VERSION 5.7 ;
  NAMESCASESENSITIVE ON ;
  NOWIREEXTENSIONATPIN ON ;
  DIVIDERCHAR "/" ;
  BUSBITCHARS "[]" ;
UNITS
  DATABASE MICRONS 200 ;
END UNITS

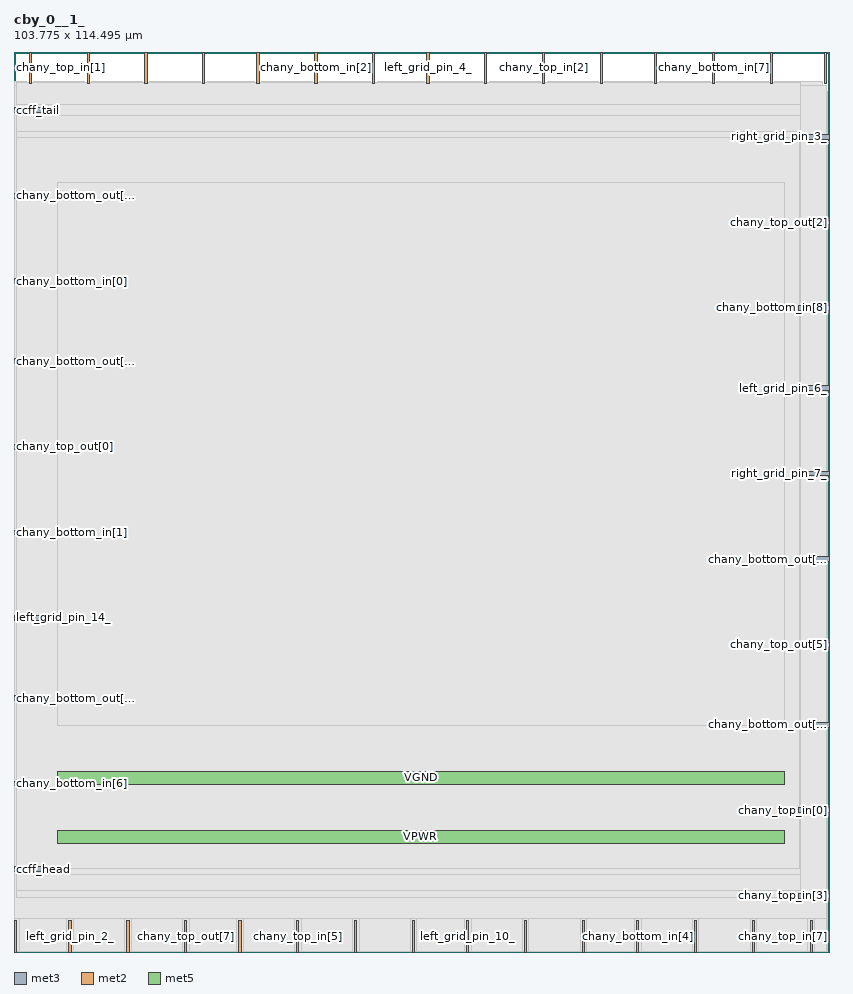
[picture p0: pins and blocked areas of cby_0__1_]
MACRO cby_0__1_
  CLASS BLOCK ;
  FOREIGN cby_0__1_ ;
  ORIGIN 0.000 0.000 ;
  SIZE 103.775 BY 114.495 ;
  PIN ccff_head
    DIRECTION INPUT ;
    PORT
      LAYER met3 ;
        RECT 0.000 10.240 4.000 10.840 ;
    END
  END ccff_head
  PIN ccff_tail
    DIRECTION OUTPUT TRISTATE ;
    PORT
      LAYER met3 ;
        RECT 0.000 106.800 4.000 107.400 ;
    END
  END ccff_tail
  PIN chany_bottom_in[0]
    DIRECTION INPUT ;
    PORT
      LAYER met3 ;
        RECT 0.000 85.040 4.000 85.640 ;
    END
  END chany_bottom_in[0]
  PIN chany_bottom_in[1]
    DIRECTION INPUT ;
    PORT
      LAYER met3 ;
        RECT 0.000 53.080 4.000 53.680 ;
    END
  END chany_bottom_in[1]
  PIN chany_bottom_in[2]
    DIRECTION INPUT ;
    PORT
      LAYER met2 ;
        RECT 38.270 110.495 38.550 114.495 ;
    END
  END chany_bottom_in[2]
  PIN chany_bottom_in[3]
    DIRECTION INPUT ;
    PORT
      LAYER met2 ;
        RECT 64.950 0.000 65.230 4.000 ;
    END
  END chany_bottom_in[3]
  PIN chany_bottom_in[4]
    DIRECTION INPUT ;
    PORT
      LAYER met2 ;
        RECT 79.210 0.000 79.490 4.000 ;
    END
  END chany_bottom_in[4]
  PIN chany_bottom_in[5]
    DIRECTION INPUT ;
    PORT
      LAYER met2 ;
        RECT 24.010 110.495 24.290 114.495 ;
    END
  END chany_bottom_in[5]
  PIN chany_bottom_in[6]
    DIRECTION INPUT ;
    PORT
      LAYER met3 ;
        RECT 0.000 21.120 4.000 21.720 ;
    END
  END chany_bottom_in[6]
  PIN chany_bottom_in[7]
    DIRECTION INPUT ;
    PORT
      LAYER met2 ;
        RECT 88.870 110.495 89.150 114.495 ;
    END
  END chany_bottom_in[7]
  PIN chany_bottom_in[8]
    DIRECTION INPUT ;
    PORT
      LAYER met3 ;
        RECT 99.775 81.640 103.775 82.240 ;
    END
  END chany_bottom_in[8]
  PIN chany_bottom_out[0]
    DIRECTION OUTPUT TRISTATE ;
    PORT
      LAYER met3 ;
        RECT 0.000 74.840 4.000 75.440 ;
    END
  END chany_bottom_out[0]
  PIN chany_bottom_out[1]
    DIRECTION OUTPUT TRISTATE ;
    PORT
      LAYER met2 ;
        RECT 86.570 0.000 86.850 4.000 ;
    END
  END chany_bottom_out[1]
  PIN chany_bottom_out[2]
    DIRECTION OUTPUT TRISTATE ;
    PORT
      LAYER met3 ;
        RECT 0.000 95.920 4.000 96.520 ;
    END
  END chany_bottom_out[2]
  PIN chany_bottom_out[3]
    DIRECTION OUTPUT TRISTATE ;
    PORT
      LAYER met2 ;
        RECT 45.630 110.495 45.910 114.495 ;
    END
  END chany_bottom_out[3]
  PIN chany_bottom_out[4]
    DIRECTION OUTPUT TRISTATE ;
    PORT
      LAYER met2 ;
        RECT 14.350 0.000 14.630 4.000 ;
    END
  END chany_bottom_out[4]
  PIN chany_bottom_out[5]
    DIRECTION OUTPUT TRISTATE ;
    PORT
      LAYER met3 ;
        RECT 99.775 28.600 103.775 29.200 ;
    END
  END chany_bottom_out[5]
  PIN chany_bottom_out[6]
    DIRECTION OUTPUT TRISTATE ;
    PORT
      LAYER met3 ;
        RECT 0.000 32.000 4.000 32.600 ;
    END
  END chany_bottom_out[6]
  PIN chany_bottom_out[7]
    DIRECTION OUTPUT TRISTATE ;
    PORT
      LAYER met3 ;
        RECT 99.775 49.680 103.775 50.280 ;
    END
  END chany_bottom_out[7]
  PIN chany_bottom_out[8]
    DIRECTION OUTPUT TRISTATE ;
    PORT
      LAYER met2 ;
        RECT 103.130 110.495 103.410 114.495 ;
    END
  END chany_bottom_out[8]
  PIN chany_top_in[0]
    DIRECTION INPUT ;
    PORT
      LAYER met3 ;
        RECT 99.775 17.720 103.775 18.320 ;
    END
  END chany_top_in[0]
  PIN chany_top_in[1]
    DIRECTION INPUT ;
    PORT
      LAYER met2 ;
        RECT 1.930 110.495 2.210 114.495 ;
    END
  END chany_top_in[1]
  PIN chany_top_in[2]
    DIRECTION INPUT ;
    PORT
      LAYER met2 ;
        RECT 67.250 110.495 67.530 114.495 ;
    END
  END chany_top_in[2]
  PIN chany_top_in[3]
    DIRECTION INPUT ;
    PORT
      LAYER met3 ;
        RECT 99.775 6.840 103.775 7.440 ;
    END
  END chany_top_in[3]
  PIN chany_top_in[4]
    DIRECTION INPUT ;
    PORT
      LAYER met2 ;
        RECT 30.910 110.495 31.190 114.495 ;
    END
  END chany_top_in[4]
  PIN chany_top_in[5]
    DIRECTION INPUT ;
    PORT
      LAYER met2 ;
        RECT 35.970 0.000 36.250 4.000 ;
    END
  END chany_top_in[5]
  PIN chany_top_in[6]
    DIRECTION INPUT ;
    PORT
      LAYER met2 ;
        RECT 16.650 110.495 16.930 114.495 ;
    END
  END chany_top_in[6]
  PIN chany_top_in[7]
    DIRECTION INPUT ;
    PORT
      LAYER met2 ;
        RECT 101.290 0.000 101.570 4.000 ;
    END
  END chany_top_in[7]
  PIN chany_top_in[8]
    DIRECTION INPUT ;
    PORT
      LAYER met2 ;
        RECT 81.510 110.495 81.790 114.495 ;
    END
  END chany_top_in[8]
  PIN chany_top_out[0]
    DIRECTION OUTPUT TRISTATE ;
    PORT
      LAYER met3 ;
        RECT 0.000 63.960 4.000 64.560 ;
    END
  END chany_top_out[0]
  PIN chany_top_out[1]
    DIRECTION OUTPUT TRISTATE ;
    PORT
      LAYER met2 ;
        RECT 50.690 0.000 50.970 4.000 ;
    END
  END chany_top_out[1]
  PIN chany_top_out[2]
    DIRECTION OUTPUT TRISTATE ;
    PORT
      LAYER met3 ;
        RECT 99.775 92.520 103.775 93.120 ;
    END
  END chany_top_out[2]
  PIN chany_top_out[3]
    DIRECTION OUTPUT TRISTATE ;
    PORT
      LAYER met2 ;
        RECT 74.610 110.495 74.890 114.495 ;
    END
  END chany_top_out[3]
  PIN chany_top_out[4]
    DIRECTION OUTPUT TRISTATE ;
    PORT
      LAYER met2 ;
        RECT 96.230 110.495 96.510 114.495 ;
    END
  END chany_top_out[4]
  PIN chany_top_out[5]
    DIRECTION OUTPUT TRISTATE ;
    PORT
      LAYER met3 ;
        RECT 99.775 38.800 103.775 39.400 ;
    END
  END chany_top_out[5]
  PIN chany_top_out[6]
    DIRECTION OUTPUT TRISTATE ;
    PORT
      LAYER met2 ;
        RECT 28.610 0.000 28.890 4.000 ;
    END
  END chany_top_out[6]
  PIN chany_top_out[7]
    DIRECTION OUTPUT TRISTATE ;
    PORT
      LAYER met2 ;
        RECT 21.710 0.000 21.990 4.000 ;
    END
  END chany_top_out[7]
  PIN chany_top_out[8]
    DIRECTION OUTPUT TRISTATE ;
    PORT
      LAYER met2 ;
        RECT 93.930 0.000 94.210 4.000 ;
    END
  END chany_top_out[8]
  PIN left_grid_pin_0_
    DIRECTION OUTPUT TRISTATE ;
    PORT
      LAYER met2 ;
        RECT 72.310 0.000 72.590 4.000 ;
    END
  END left_grid_pin_0_
  PIN left_grid_pin_10_
    DIRECTION OUTPUT TRISTATE ;
    PORT
      LAYER met2 ;
        RECT 57.590 0.000 57.870 4.000 ;
    END
  END left_grid_pin_10_
  PIN left_grid_pin_12_
    DIRECTION OUTPUT TRISTATE ;
    PORT
      LAYER met2 ;
        RECT 43.330 0.000 43.610 4.000 ;
    END
  END left_grid_pin_12_
  PIN left_grid_pin_14_
    DIRECTION OUTPUT TRISTATE ;
    PORT
      LAYER met3 ;
        RECT 0.000 42.200 4.000 42.800 ;
    END
  END left_grid_pin_14_
  PIN left_grid_pin_2_
    DIRECTION OUTPUT TRISTATE ;
    PORT
      LAYER met2 ;
        RECT 6.990 0.000 7.270 4.000 ;
    END
  END left_grid_pin_2_
  PIN left_grid_pin_4_
    DIRECTION OUTPUT TRISTATE ;
    PORT
      LAYER met2 ;
        RECT 52.530 110.495 52.810 114.495 ;
    END
  END left_grid_pin_4_
  PIN left_grid_pin_6_
    DIRECTION OUTPUT TRISTATE ;
    PORT
      LAYER met3 ;
        RECT 99.775 71.440 103.775 72.040 ;
    END
  END left_grid_pin_6_
  PIN left_grid_pin_8_
    DIRECTION OUTPUT TRISTATE ;
    PORT
      LAYER met2 ;
        RECT 0.090 0.000 0.370 4.000 ;
    END
  END left_grid_pin_8_
  PIN pReset
    DIRECTION INPUT ;
    PORT
      LAYER met2 ;
        RECT 9.290 110.495 9.570 114.495 ;
    END
  END pReset
  PIN prog_clk
    DIRECTION INPUT ;
    PORT
      LAYER met2 ;
        RECT 59.890 110.495 60.170 114.495 ;
    END
  END prog_clk
  PIN right_grid_pin_3_
    DIRECTION OUTPUT TRISTATE ;
    PORT
      LAYER met3 ;
        RECT 99.775 103.400 103.775 104.000 ;
    END
  END right_grid_pin_3_
  PIN right_grid_pin_7_
    DIRECTION OUTPUT TRISTATE ;
    PORT
      LAYER met3 ;
        RECT 99.775 60.560 103.775 61.160 ;
    END
  END right_grid_pin_7_
  PIN VPWR
    DIRECTION INPUT ;
    USE POWER ;
    PORT
      LAYER met5 ;
        RECT 5.520 13.840 97.980 15.440 ;
    END
  END VPWR
  PIN VGND
    DIRECTION INPUT ;
    USE GROUND ;
    PORT
      LAYER met5 ;
        RECT 5.520 21.340 97.980 22.940 ;
    END
  END VGND
  OBS
      LAYER li1 ;
        RECT 5.520 10.795 97.980 103.445 ;
      LAYER met1 ;
        RECT 0.070 0.040 103.430 109.440 ;
      LAYER met2 ;
        RECT 0.090 110.215 1.650 110.685 ;
        RECT 2.490 110.215 9.010 110.685 ;
        RECT 9.850 110.215 16.370 110.685 ;
        RECT 17.210 110.215 23.730 110.685 ;
        RECT 24.570 110.215 30.630 110.685 ;
        RECT 31.470 110.215 37.990 110.685 ;
        RECT 38.830 110.215 45.350 110.685 ;
        RECT 46.190 110.215 52.250 110.685 ;
        RECT 53.090 110.215 59.610 110.685 ;
        RECT 60.450 110.215 66.970 110.685 ;
        RECT 67.810 110.215 74.330 110.685 ;
        RECT 75.170 110.215 81.230 110.685 ;
        RECT 82.070 110.215 88.590 110.685 ;
        RECT 89.430 110.215 95.950 110.685 ;
        RECT 96.790 110.215 102.850 110.685 ;
        RECT 0.090 4.280 103.400 110.215 ;
        RECT 0.650 0.010 6.710 4.280 ;
        RECT 7.550 0.010 14.070 4.280 ;
        RECT 14.910 0.010 21.430 4.280 ;
        RECT 22.270 0.010 28.330 4.280 ;
        RECT 29.170 0.010 35.690 4.280 ;
        RECT 36.530 0.010 43.050 4.280 ;
        RECT 43.890 0.010 50.410 4.280 ;
        RECT 51.250 0.010 57.310 4.280 ;
        RECT 58.150 0.010 64.670 4.280 ;
        RECT 65.510 0.010 72.030 4.280 ;
        RECT 72.870 0.010 78.930 4.280 ;
        RECT 79.770 0.010 86.290 4.280 ;
        RECT 87.130 0.010 93.650 4.280 ;
        RECT 94.490 0.010 101.010 4.280 ;
        RECT 101.850 0.010 103.400 4.280 ;
      LAYER met3 ;
        RECT 0.270 107.800 100.010 110.665 ;
        RECT 4.400 106.400 100.010 107.800 ;
        RECT 0.270 104.400 100.010 106.400 ;
        RECT 0.270 103.000 99.375 104.400 ;
        RECT 0.270 96.920 100.010 103.000 ;
        RECT 4.400 95.520 100.010 96.920 ;
        RECT 0.270 93.520 100.010 95.520 ;
        RECT 0.270 92.120 99.375 93.520 ;
        RECT 0.270 86.040 100.010 92.120 ;
        RECT 4.400 84.640 100.010 86.040 ;
        RECT 0.270 82.640 100.010 84.640 ;
        RECT 0.270 81.240 99.375 82.640 ;
        RECT 0.270 75.840 100.010 81.240 ;
        RECT 4.400 74.440 100.010 75.840 ;
        RECT 0.270 72.440 100.010 74.440 ;
        RECT 0.270 71.040 99.375 72.440 ;
        RECT 0.270 64.960 100.010 71.040 ;
        RECT 4.400 63.560 100.010 64.960 ;
        RECT 0.270 61.560 100.010 63.560 ;
        RECT 0.270 60.160 99.375 61.560 ;
        RECT 0.270 54.080 100.010 60.160 ;
        RECT 4.400 52.680 100.010 54.080 ;
        RECT 0.270 50.680 100.010 52.680 ;
        RECT 0.270 49.280 99.375 50.680 ;
        RECT 0.270 43.200 100.010 49.280 ;
        RECT 4.400 41.800 100.010 43.200 ;
        RECT 0.270 39.800 100.010 41.800 ;
        RECT 0.270 38.400 99.375 39.800 ;
        RECT 0.270 33.000 100.010 38.400 ;
        RECT 4.400 31.600 100.010 33.000 ;
        RECT 0.270 29.600 100.010 31.600 ;
        RECT 0.270 28.200 99.375 29.600 ;
        RECT 0.270 22.120 100.010 28.200 ;
        RECT 4.400 20.720 100.010 22.120 ;
        RECT 0.270 18.720 100.010 20.720 ;
        RECT 0.270 17.320 99.375 18.720 ;
        RECT 0.270 11.240 100.010 17.320 ;
        RECT 4.400 9.840 100.010 11.240 ;
        RECT 0.270 7.840 100.010 9.840 ;
        RECT 0.270 6.975 99.375 7.840 ;
      LAYER met4 ;
        RECT 0.295 10.640 99.985 103.600 ;
      LAYER met5 ;
        RECT 5.520 28.840 97.980 97.940 ;
  END
END cby_0__1_
END LIBRARY

